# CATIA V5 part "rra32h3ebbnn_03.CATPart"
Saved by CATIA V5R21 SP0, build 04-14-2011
Part number: rra32h3ebbnn_03
Bounding box of the stored display mesh (mm): x -11.506 to 11.506, y -11.331 to 11.506, z -24.79 to 3.183
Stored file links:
  C:\TPO v2\SharedFS\Outgoing\rra32h3ebbnn_03.CATPart

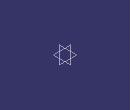
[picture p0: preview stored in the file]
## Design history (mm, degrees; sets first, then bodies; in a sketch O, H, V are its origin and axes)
AxisSystem1: origin (0, 0, 0), X (1, 0, 0), Y (0, 1, 0), Z (0, 0, 1)
Body1 "rra32h3ebbnn_03" (main body)
  Solid1: solid without history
